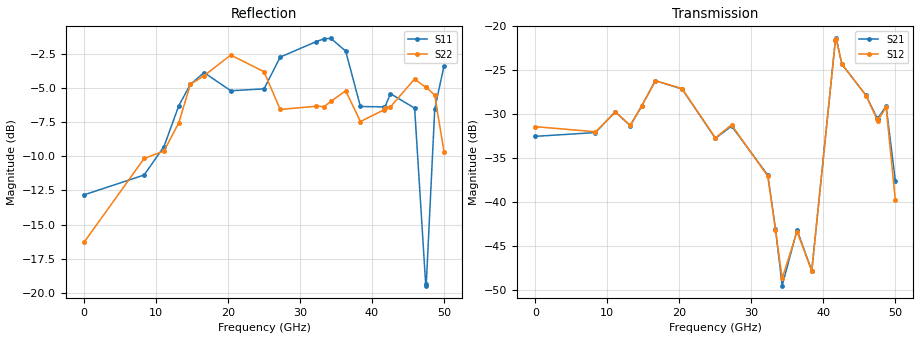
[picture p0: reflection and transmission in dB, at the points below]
!Keysight Technologies,N5245B,MY58422270,A.16.20.02
!Date: Thursday, March 05, 2026 01:43:13
!Correction: S11(C  2-Port  )
!S21(C  2-Port  )
!S12(C  2-Port  )
!S22(C  2-Port  )
!S2P File: Measurements: S11, S21, S12, S22:
# Hz S  dB  R 50
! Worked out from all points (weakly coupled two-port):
!   3201 points, 10 MHz to 50 GHz, reference 50 ohm
!   highest |S21| = -21.38 dB at 41.8 GHz (marker M1); lowest = -49.5 dB at 34.28 GHz (marker M2)
!   lowest |S11| = -19.5 dB at 47.53 GHz (marker M3), VSWR 1.24, Z = 45.8 + j9.32 ohm
!   |S11| at or under -10 dB: start of sweep to 10.03 GHz; 11.36 GHz to 11.93 GHz (572.5 MHz wide, 4.92 % of centre); 46.69 GHz to 48.24 GHz (1.554 GHz wide, 3.28 % of centre)
!   |S22| runs from -21.3 to -2.5 dB; largest |S21 - S12| = 0.0064
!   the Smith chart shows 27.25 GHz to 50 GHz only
!   S11 on the Smith chart (normalised r, x): 27.25 GHz: 0.18, +0.36; 32.28 GHz: 0.42, +1.84; 36.35 GHz: 2.43, -3.42; 42.56 GHz: 0.94, -1.23; 47.45 GHz: 0.87, +0.15; 50 GHz: 0.62, -1.39
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1e7  -12.83 -4.1  -32.52 10.6  -31.42 -2.0  -16.30 42.3
8.352081e9  -11.38 175.0  -32.09 35.7  -32.00 35.4  -10.17 -176.0
1.110153e10  -9.31 107.8  -29.72 -58.8  -29.77 -58.8  -9.63 84.5
1.317924e10  -6.30 63.1  -31.32 -111.2  -31.24 -111.7  -7.55 -23.1
1.477267e10  -4.76 12.3  -29.06 -144.9  -29.06 -144.9  -4.75 -91.4
1.667854e10  -3.89 -43.9  -26.19 159.5  -26.20 159.3  -4.12 -142.6
2.038092e10  -5.22 -121.1  -27.14 41.5  -27.09 41.1  -2.61 153.6
2.5005e10  -5.08 -178.9  -32.75 -64.7  -32.69 -65.1  -3.83 71.1
2.725455e10  -2.76 139.2  -31.36 -113.8  -31.21 -114.3  -6.59 31.9
3.228479e10  -1.62 55.1  -36.93 48.7  -37.06 47.6  -6.35 -105.3
3.334708e10  -1.42 35.9  -43.01 4.6  -43.12 5.0  -6.38 -129.7
3.428439e10  -1.39 19.3  -49.50 -75.8  -48.66 -78.0  -6.00 -150.0
3.634648e10  -2.32 -22.4  -43.17 114.5  -43.36 113.4  -5.22 170.1
3.839295e10  -6.37 -22.5  -47.80 -100.9  -47.82 -114.5  -7.47 137.6
4.167354e10  -6.40 -53.1  -21.60 -54.9  -21.58 -55.3  -6.61 112.4
4.179852e10  -6.40 -53.1  -21.38 -66.5  -21.44 -67.2  -6.51 111.4
4.256399e10  -5.43 -60.3  -24.30 -119.7  -24.28 -118.6  -6.40 107.4
4.592269e10  -6.49 -116.6  -27.86 47.0  -27.88 46.8  -4.36 62.3
4.745363e10  -19.32 127.0  -30.42 -10.1  -30.60 -9.1  -4.97 43.5
4.753174e10  -19.47 108.8  -30.52 -11.3  -30.76 -10.2  -4.95 42.6
4.871901e10  -6.54 -22.0  -29.08 -86.8  -29.21 -86.6  -5.56 20.1
5e10  -3.41 -64.6  -37.57 -120.3  -39.76 -131.9  -9.68 6.8
